# Generated deterministically by seda-macro-lef-normalizer-v1; recipe orfs-asap7-fakeram-m4-v1.
VERSION 5.8 ;
BUSBITCHARS "[]" ;
DIVIDERCHAR "/" ;

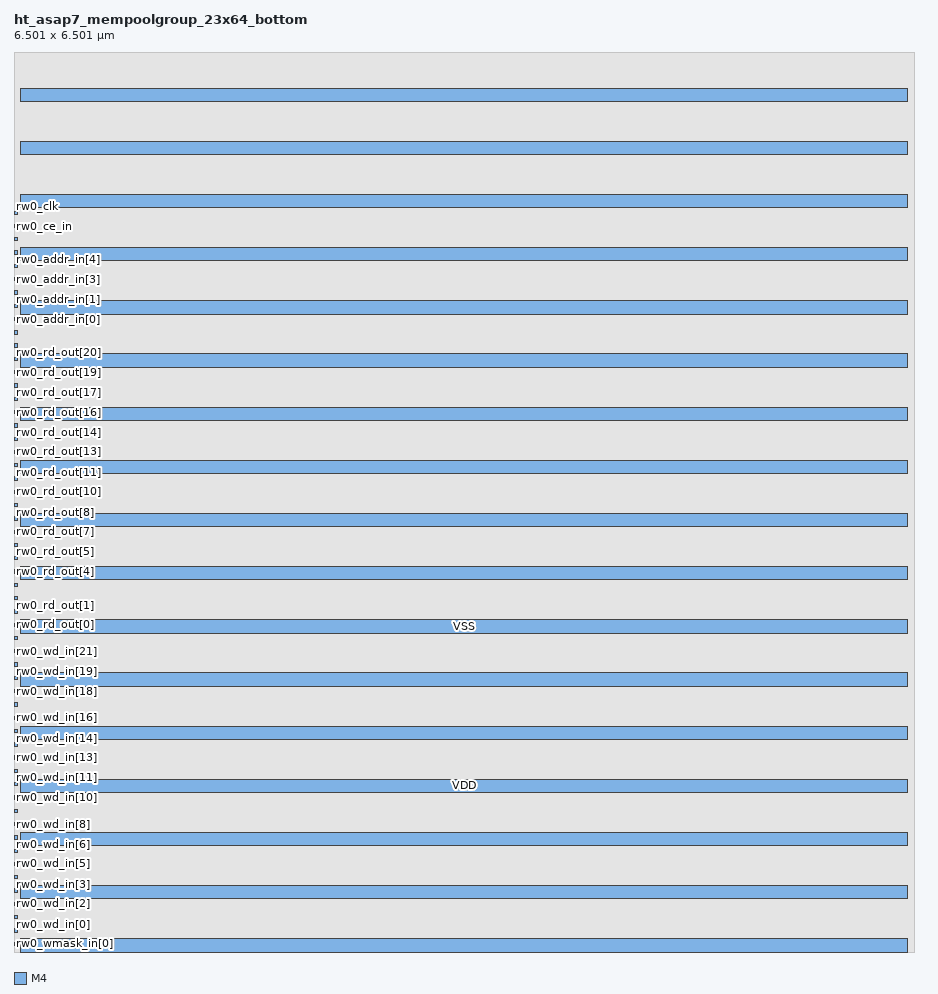
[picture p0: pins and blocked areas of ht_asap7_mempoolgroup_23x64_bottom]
MACRO ht_asap7_mempoolgroup_23x64_bottom
  FOREIGN ht_asap7_mempoolgroup_23x64_bottom 0 0 ;
  CLASS BLOCK ;
  ORIGIN 0 0 ;
  SIZE 6.501 BY 6.501 ;
  SYMMETRY X Y R90 ;
  PIN rw0_wmask_in[0]
    DIRECTION INPUT ;
    USE SIGNAL ;
    SHAPE ABUTMENT ;
    PORT
      LAYER M4 ;
      RECT 0 0.048 0.024 0.072 ;
    END
  END rw0_wmask_in[0]
  PIN rw0_wd_in[0]
    DIRECTION INPUT ;
    USE SIGNAL ;
    SHAPE ABUTMENT ;
    PORT
      LAYER M4 ;
      RECT 0 0.144 0.024 0.168 ;
    END
  END rw0_wd_in[0]
  PIN rw0_wd_in[1]
    DIRECTION INPUT ;
    USE SIGNAL ;
    SHAPE ABUTMENT ;
    PORT
      LAYER M4 ;
      RECT 0 0.24 0.024 0.264 ;
    END
  END rw0_wd_in[1]
  PIN rw0_wd_in[2]
    DIRECTION INPUT ;
    USE SIGNAL ;
    SHAPE ABUTMENT ;
    PORT
      LAYER M4 ;
      RECT 0 0.336 0.024 0.36 ;
    END
  END rw0_wd_in[2]
  PIN rw0_wd_in[3]
    DIRECTION INPUT ;
    USE SIGNAL ;
    SHAPE ABUTMENT ;
    PORT
      LAYER M4 ;
      RECT 0 0.432 0.024 0.456 ;
    END
  END rw0_wd_in[3]
  PIN rw0_wd_in[4]
    DIRECTION INPUT ;
    USE SIGNAL ;
    SHAPE ABUTMENT ;
    PORT
      LAYER M4 ;
      RECT 0 0.528 0.024 0.552 ;
    END
  END rw0_wd_in[4]
  PIN rw0_wd_in[5]
    DIRECTION INPUT ;
    USE SIGNAL ;
    SHAPE ABUTMENT ;
    PORT
      LAYER M4 ;
      RECT 0 0.624 0.024 0.648 ;
    END
  END rw0_wd_in[5]
  PIN rw0_wd_in[6]
    DIRECTION INPUT ;
    USE SIGNAL ;
    SHAPE ABUTMENT ;
    PORT
      LAYER M4 ;
      RECT 0 0.72 0.024 0.744 ;
    END
  END rw0_wd_in[6]
  PIN rw0_wd_in[7]
    DIRECTION INPUT ;
    USE SIGNAL ;
    SHAPE ABUTMENT ;
    PORT
      LAYER M4 ;
      RECT 0 0.816 0.024 0.84 ;
    END
  END rw0_wd_in[7]
  PIN rw0_wd_in[8]
    DIRECTION INPUT ;
    USE SIGNAL ;
    SHAPE ABUTMENT ;
    PORT
      LAYER M4 ;
      RECT 0 0.912 0.024 0.936 ;
    END
  END rw0_wd_in[8]
  PIN rw0_wd_in[9]
    DIRECTION INPUT ;
    USE SIGNAL ;
    SHAPE ABUTMENT ;
    PORT
      LAYER M4 ;
      RECT 0 1.008 0.024 1.032 ;
    END
  END rw0_wd_in[9]
  PIN rw0_wd_in[10]
    DIRECTION INPUT ;
    USE SIGNAL ;
    SHAPE ABUTMENT ;
    PORT
      LAYER M4 ;
      RECT 0 1.104 0.024 1.128 ;
    END
  END rw0_wd_in[10]
  PIN rw0_wd_in[11]
    DIRECTION INPUT ;
    USE SIGNAL ;
    SHAPE ABUTMENT ;
    PORT
      LAYER M4 ;
      RECT 0 1.2 0.024 1.224 ;
    END
  END rw0_wd_in[11]
  PIN rw0_wd_in[12]
    DIRECTION INPUT ;
    USE SIGNAL ;
    SHAPE ABUTMENT ;
    PORT
      LAYER M4 ;
      RECT 0 1.296 0.024 1.32 ;
    END
  END rw0_wd_in[12]
  PIN rw0_wd_in[13]
    DIRECTION INPUT ;
    USE SIGNAL ;
    SHAPE ABUTMENT ;
    PORT
      LAYER M4 ;
      RECT 0 1.392 0.024 1.416 ;
    END
  END rw0_wd_in[13]
  PIN rw0_wd_in[14]
    DIRECTION INPUT ;
    USE SIGNAL ;
    SHAPE ABUTMENT ;
    PORT
      LAYER M4 ;
      RECT 0 1.488 0.024 1.512 ;
    END
  END rw0_wd_in[14]
  PIN rw0_wd_in[15]
    DIRECTION INPUT ;
    USE SIGNAL ;
    SHAPE ABUTMENT ;
    PORT
      LAYER M4 ;
      RECT 0 1.584 0.024 1.608 ;
    END
  END rw0_wd_in[15]
  PIN rw0_wd_in[16]
    DIRECTION INPUT ;
    USE SIGNAL ;
    SHAPE ABUTMENT ;
    PORT
      LAYER M4 ;
      RECT 0 1.68 0.024 1.704 ;
    END
  END rw0_wd_in[16]
  PIN rw0_wd_in[17]
    DIRECTION INPUT ;
    USE SIGNAL ;
    SHAPE ABUTMENT ;
    PORT
      LAYER M4 ;
      RECT 0 1.776 0.024 1.8 ;
    END
  END rw0_wd_in[17]
  PIN rw0_wd_in[18]
    DIRECTION INPUT ;
    USE SIGNAL ;
    SHAPE ABUTMENT ;
    PORT
      LAYER M4 ;
      RECT 0 1.872 0.024 1.896 ;
    END
  END rw0_wd_in[18]
  PIN rw0_wd_in[19]
    DIRECTION INPUT ;
    USE SIGNAL ;
    SHAPE ABUTMENT ;
    PORT
      LAYER M4 ;
      RECT 0 1.968 0.024 1.992 ;
    END
  END rw0_wd_in[19]
  PIN rw0_wd_in[20]
    DIRECTION INPUT ;
    USE SIGNAL ;
    SHAPE ABUTMENT ;
    PORT
      LAYER M4 ;
      RECT 0 2.064 0.024 2.088 ;
    END
  END rw0_wd_in[20]
  PIN rw0_wd_in[21]
    DIRECTION INPUT ;
    USE SIGNAL ;
    SHAPE ABUTMENT ;
    PORT
      LAYER M4 ;
      RECT 0 2.16 0.024 2.184 ;
    END
  END rw0_wd_in[21]
  PIN rw0_wd_in[22]
    DIRECTION INPUT ;
    USE SIGNAL ;
    SHAPE ABUTMENT ;
    PORT
      LAYER M4 ;
      RECT 0 2.256 0.024 2.28 ;
    END
  END rw0_wd_in[22]
  PIN rw0_rd_out[0]
    DIRECTION OUTPUT ;
    USE SIGNAL ;
    SHAPE ABUTMENT ;
    PORT
      LAYER M4 ;
      RECT 0 2.352 0.024 2.376 ;
    END
  END rw0_rd_out[0]
  PIN rw0_rd_out[1]
    DIRECTION OUTPUT ;
    USE SIGNAL ;
    SHAPE ABUTMENT ;
    PORT
      LAYER M4 ;
      RECT 0 2.448 0.024 2.472 ;
    END
  END rw0_rd_out[1]
  PIN rw0_rd_out[2]
    DIRECTION OUTPUT ;
    USE SIGNAL ;
    SHAPE ABUTMENT ;
    PORT
      LAYER M4 ;
      RECT 0 2.544 0.024 2.568 ;
    END
  END rw0_rd_out[2]
  PIN rw0_rd_out[3]
    DIRECTION OUTPUT ;
    USE SIGNAL ;
    SHAPE ABUTMENT ;
    PORT
      LAYER M4 ;
      RECT 0 2.64 0.024 2.664 ;
    END
  END rw0_rd_out[3]
  PIN rw0_rd_out[4]
    DIRECTION OUTPUT ;
    USE SIGNAL ;
    SHAPE ABUTMENT ;
    PORT
      LAYER M4 ;
      RECT 0 2.736 0.024 2.76 ;
    END
  END rw0_rd_out[4]
  PIN rw0_rd_out[5]
    DIRECTION OUTPUT ;
    USE SIGNAL ;
    SHAPE ABUTMENT ;
    PORT
      LAYER M4 ;
      RECT 0 2.832 0.024 2.856 ;
    END
  END rw0_rd_out[5]
  PIN rw0_rd_out[6]
    DIRECTION OUTPUT ;
    USE SIGNAL ;
    SHAPE ABUTMENT ;
    PORT
      LAYER M4 ;
      RECT 0 2.928 0.024 2.952 ;
    END
  END rw0_rd_out[6]
  PIN rw0_rd_out[7]
    DIRECTION OUTPUT ;
    USE SIGNAL ;
    SHAPE ABUTMENT ;
    PORT
      LAYER M4 ;
      RECT 0 3.024 0.024 3.048 ;
    END
  END rw0_rd_out[7]
  PIN rw0_rd_out[8]
    DIRECTION OUTPUT ;
    USE SIGNAL ;
    SHAPE ABUTMENT ;
    PORT
      LAYER M4 ;
      RECT 0 3.12 0.024 3.144 ;
    END
  END rw0_rd_out[8]
  PIN rw0_rd_out[9]
    DIRECTION OUTPUT ;
    USE SIGNAL ;
    SHAPE ABUTMENT ;
    PORT
      LAYER M4 ;
      RECT 0 3.216 0.024 3.24 ;
    END
  END rw0_rd_out[9]
  PIN rw0_rd_out[10]
    DIRECTION OUTPUT ;
    USE SIGNAL ;
    SHAPE ABUTMENT ;
    PORT
      LAYER M4 ;
      RECT 0 3.312 0.024 3.336 ;
    END
  END rw0_rd_out[10]
  PIN rw0_rd_out[11]
    DIRECTION OUTPUT ;
    USE SIGNAL ;
    SHAPE ABUTMENT ;
    PORT
      LAYER M4 ;
      RECT 0 3.408 0.024 3.432 ;
    END
  END rw0_rd_out[11]
  PIN rw0_rd_out[12]
    DIRECTION OUTPUT ;
    USE SIGNAL ;
    SHAPE ABUTMENT ;
    PORT
      LAYER M4 ;
      RECT 0 3.504 0.024 3.528 ;
    END
  END rw0_rd_out[12]
  PIN rw0_rd_out[13]
    DIRECTION OUTPUT ;
    USE SIGNAL ;
    SHAPE ABUTMENT ;
    PORT
      LAYER M4 ;
      RECT 0 3.6 0.024 3.624 ;
    END
  END rw0_rd_out[13]
  PIN rw0_rd_out[14]
    DIRECTION OUTPUT ;
    USE SIGNAL ;
    SHAPE ABUTMENT ;
    PORT
      LAYER M4 ;
      RECT 0 3.696 0.024 3.72 ;
    END
  END rw0_rd_out[14]
  PIN rw0_rd_out[15]
    DIRECTION OUTPUT ;
    USE SIGNAL ;
    SHAPE ABUTMENT ;
    PORT
      LAYER M4 ;
      RECT 0 3.792 0.024 3.816 ;
    END
  END rw0_rd_out[15]
  PIN rw0_rd_out[16]
    DIRECTION OUTPUT ;
    USE SIGNAL ;
    SHAPE ABUTMENT ;
    PORT
      LAYER M4 ;
      RECT 0 3.888 0.024 3.912 ;
    END
  END rw0_rd_out[16]
  PIN rw0_rd_out[17]
    DIRECTION OUTPUT ;
    USE SIGNAL ;
    SHAPE ABUTMENT ;
    PORT
      LAYER M4 ;
      RECT 0 3.984 0.024 4.008 ;
    END
  END rw0_rd_out[17]
  PIN rw0_rd_out[18]
    DIRECTION OUTPUT ;
    USE SIGNAL ;
    SHAPE ABUTMENT ;
    PORT
      LAYER M4 ;
      RECT 0 4.08 0.024 4.104 ;
    END
  END rw0_rd_out[18]
  PIN rw0_rd_out[19]
    DIRECTION OUTPUT ;
    USE SIGNAL ;
    SHAPE ABUTMENT ;
    PORT
      LAYER M4 ;
      RECT 0 4.176 0.024 4.2 ;
    END
  END rw0_rd_out[19]
  PIN rw0_rd_out[20]
    DIRECTION OUTPUT ;
    USE SIGNAL ;
    SHAPE ABUTMENT ;
    PORT
      LAYER M4 ;
      RECT 0 4.272 0.024 4.296 ;
    END
  END rw0_rd_out[20]
  PIN rw0_rd_out[21]
    DIRECTION OUTPUT ;
    USE SIGNAL ;
    SHAPE ABUTMENT ;
    PORT
      LAYER M4 ;
      RECT 0 4.368 0.024 4.392 ;
    END
  END rw0_rd_out[21]
  PIN rw0_rd_out[22]
    DIRECTION OUTPUT ;
    USE SIGNAL ;
    SHAPE ABUTMENT ;
    PORT
      LAYER M4 ;
      RECT 0 4.464 0.024 4.488 ;
    END
  END rw0_rd_out[22]
  PIN rw0_addr_in[0]
    DIRECTION INPUT ;
    USE SIGNAL ;
    SHAPE ABUTMENT ;
    PORT
      LAYER M4 ;
      RECT 0 4.56 0.024 4.584 ;
    END
  END rw0_addr_in[0]
  PIN rw0_addr_in[1]
    DIRECTION INPUT ;
    USE SIGNAL ;
    SHAPE ABUTMENT ;
    PORT
      LAYER M4 ;
      RECT 0 4.656 0.024 4.68 ;
    END
  END rw0_addr_in[1]
  PIN rw0_addr_in[2]
    DIRECTION INPUT ;
    USE SIGNAL ;
    SHAPE ABUTMENT ;
    PORT
      LAYER M4 ;
      RECT 0 4.752 0.024 4.776 ;
    END
  END rw0_addr_in[2]
  PIN rw0_addr_in[3]
    DIRECTION INPUT ;
    USE SIGNAL ;
    SHAPE ABUTMENT ;
    PORT
      LAYER M4 ;
      RECT 0 4.848 0.024 4.872 ;
    END
  END rw0_addr_in[3]
  PIN rw0_addr_in[4]
    DIRECTION INPUT ;
    USE SIGNAL ;
    SHAPE ABUTMENT ;
    PORT
      LAYER M4 ;
      RECT 0 4.944 0.024 4.968 ;
    END
  END rw0_addr_in[4]
  PIN rw0_addr_in[5]
    DIRECTION INPUT ;
    USE SIGNAL ;
    SHAPE ABUTMENT ;
    PORT
      LAYER M4 ;
      RECT 0 5.04 0.024 5.064 ;
    END
  END rw0_addr_in[5]
  PIN rw0_we_in
    DIRECTION INPUT ;
    USE SIGNAL ;
    SHAPE ABUTMENT ;
    PORT
      LAYER M4 ;
      RECT 0 5.136 0.024 5.16 ;
    END
  END rw0_we_in
  PIN rw0_ce_in
    DIRECTION INPUT ;
    USE SIGNAL ;
    SHAPE ABUTMENT ;
    PORT
      LAYER M4 ;
      RECT 0 5.232 0.024 5.256 ;
    END
  END rw0_ce_in
  PIN rw0_clk
    DIRECTION INPUT ;
    USE SIGNAL ;
    SHAPE ABUTMENT ;
    PORT
      LAYER M4 ;
      RECT 0 5.328 0.024 5.352 ;
    END
  END rw0_clk
  PIN VSS
    DIRECTION INOUT ;
    USE GROUND ;
    PORT
      LAYER M4 ;
      RECT 0.048 0 6.453 0.096 ;
      RECT 0.048 0.768 6.453 0.864 ;
      RECT 0.048 1.536 6.453 1.632 ;
      RECT 0.048 2.304 6.453 2.4 ;
      RECT 0.048 3.072 6.453 3.168 ;
      RECT 0.048 3.84 6.453 3.936 ;
      RECT 0.048 4.608 6.453 4.704 ;
      RECT 0.048 5.376 6.453 5.472 ;
      RECT 0.048 6.144 6.453 6.24 ;
    END
  END VSS
  PIN VDD
    DIRECTION INOUT ;
    USE POWER ;
    PORT
      LAYER M4 ;
      RECT 0.048 0.384 6.453 0.48 ;
      RECT 0.048 1.152 6.453 1.248 ;
      RECT 0.048 1.92 6.453 2.016 ;
      RECT 0.048 2.688 6.453 2.784 ;
      RECT 0.048 3.456 6.453 3.552 ;
      RECT 0.048 4.224 6.453 4.32 ;
      RECT 0.048 4.992 6.453 5.088 ;
      RECT 0.048 5.76 6.453 5.856 ;
    END
  END VDD
  OBS
    LAYER M1 ;
    RECT 0 0 6.501 6.501 ;
    LAYER M2 ;
    RECT 0 0 6.501 6.501 ;
    LAYER M3 ;
    RECT 0 0 6.501 6.501 ;
  END
END ht_asap7_mempoolgroup_23x64_bottom

END LIBRARY
